VERSION 5.8 ;
BUSBITCHARS "[]" ;
DIVIDERCHAR "/" ;
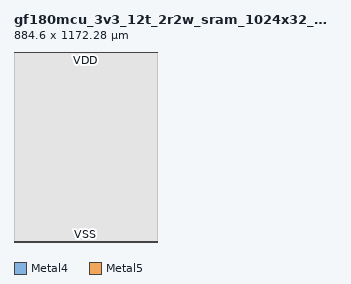
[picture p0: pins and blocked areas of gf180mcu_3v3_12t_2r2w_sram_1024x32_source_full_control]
MACRO gf180mcu_3v3_12t_2r2w_sram_1024x32_source_full_control
  CLASS BLOCK ;
  FOREIGN gf180mcu_3v3_12t_2r2w_sram_1024x32_source_full_control 0.000 0.000 ;
  ORIGIN 0.000 0.000 ;
  SIZE 884.600000 BY 1172.280000 ;
  SYMMETRY X Y ;
  PIN VDD
    DIRECTION INOUT ;
    USE POWER ;
    PORT
      LAYER Metal4 ;
        RECT 0.000000 1171.280000 884.600000 1172.280000 ;
      LAYER Metal5 ;
        RECT 0.000000 1171.280000 884.600000 1172.280000 ;
    END
  END VDD
  PIN VSS
    DIRECTION INOUT ;
    USE GROUND ;
    PORT
      LAYER Metal4 ;
        RECT 0.000000 0.000000 884.600000 1.000000 ;
      LAYER Metal5 ;
        RECT 0.000000 0.000000 884.600000 1.000000 ;
    END
  END VSS
  OBS
    LAYER Metal1 ;
      RECT 0.000000 0.000000 884.600000 1172.280000 ;
    LAYER Metal2 ;
      RECT 0.000000 0.000000 884.600000 1172.280000 ;
    LAYER Metal3 ;
      RECT 0.000000 1.200000 884.600000 1171.080000 ;
    LAYER Metal4 ;
      RECT 0.000000 1.200000 884.600000 1171.080000 ;
    LAYER Metal5 ;
      RECT 0.000000 1.200000 884.600000 1171.080000 ;
  END
END gf180mcu_3v3_12t_2r2w_sram_1024x32_source_full_control
END LIBRARY
